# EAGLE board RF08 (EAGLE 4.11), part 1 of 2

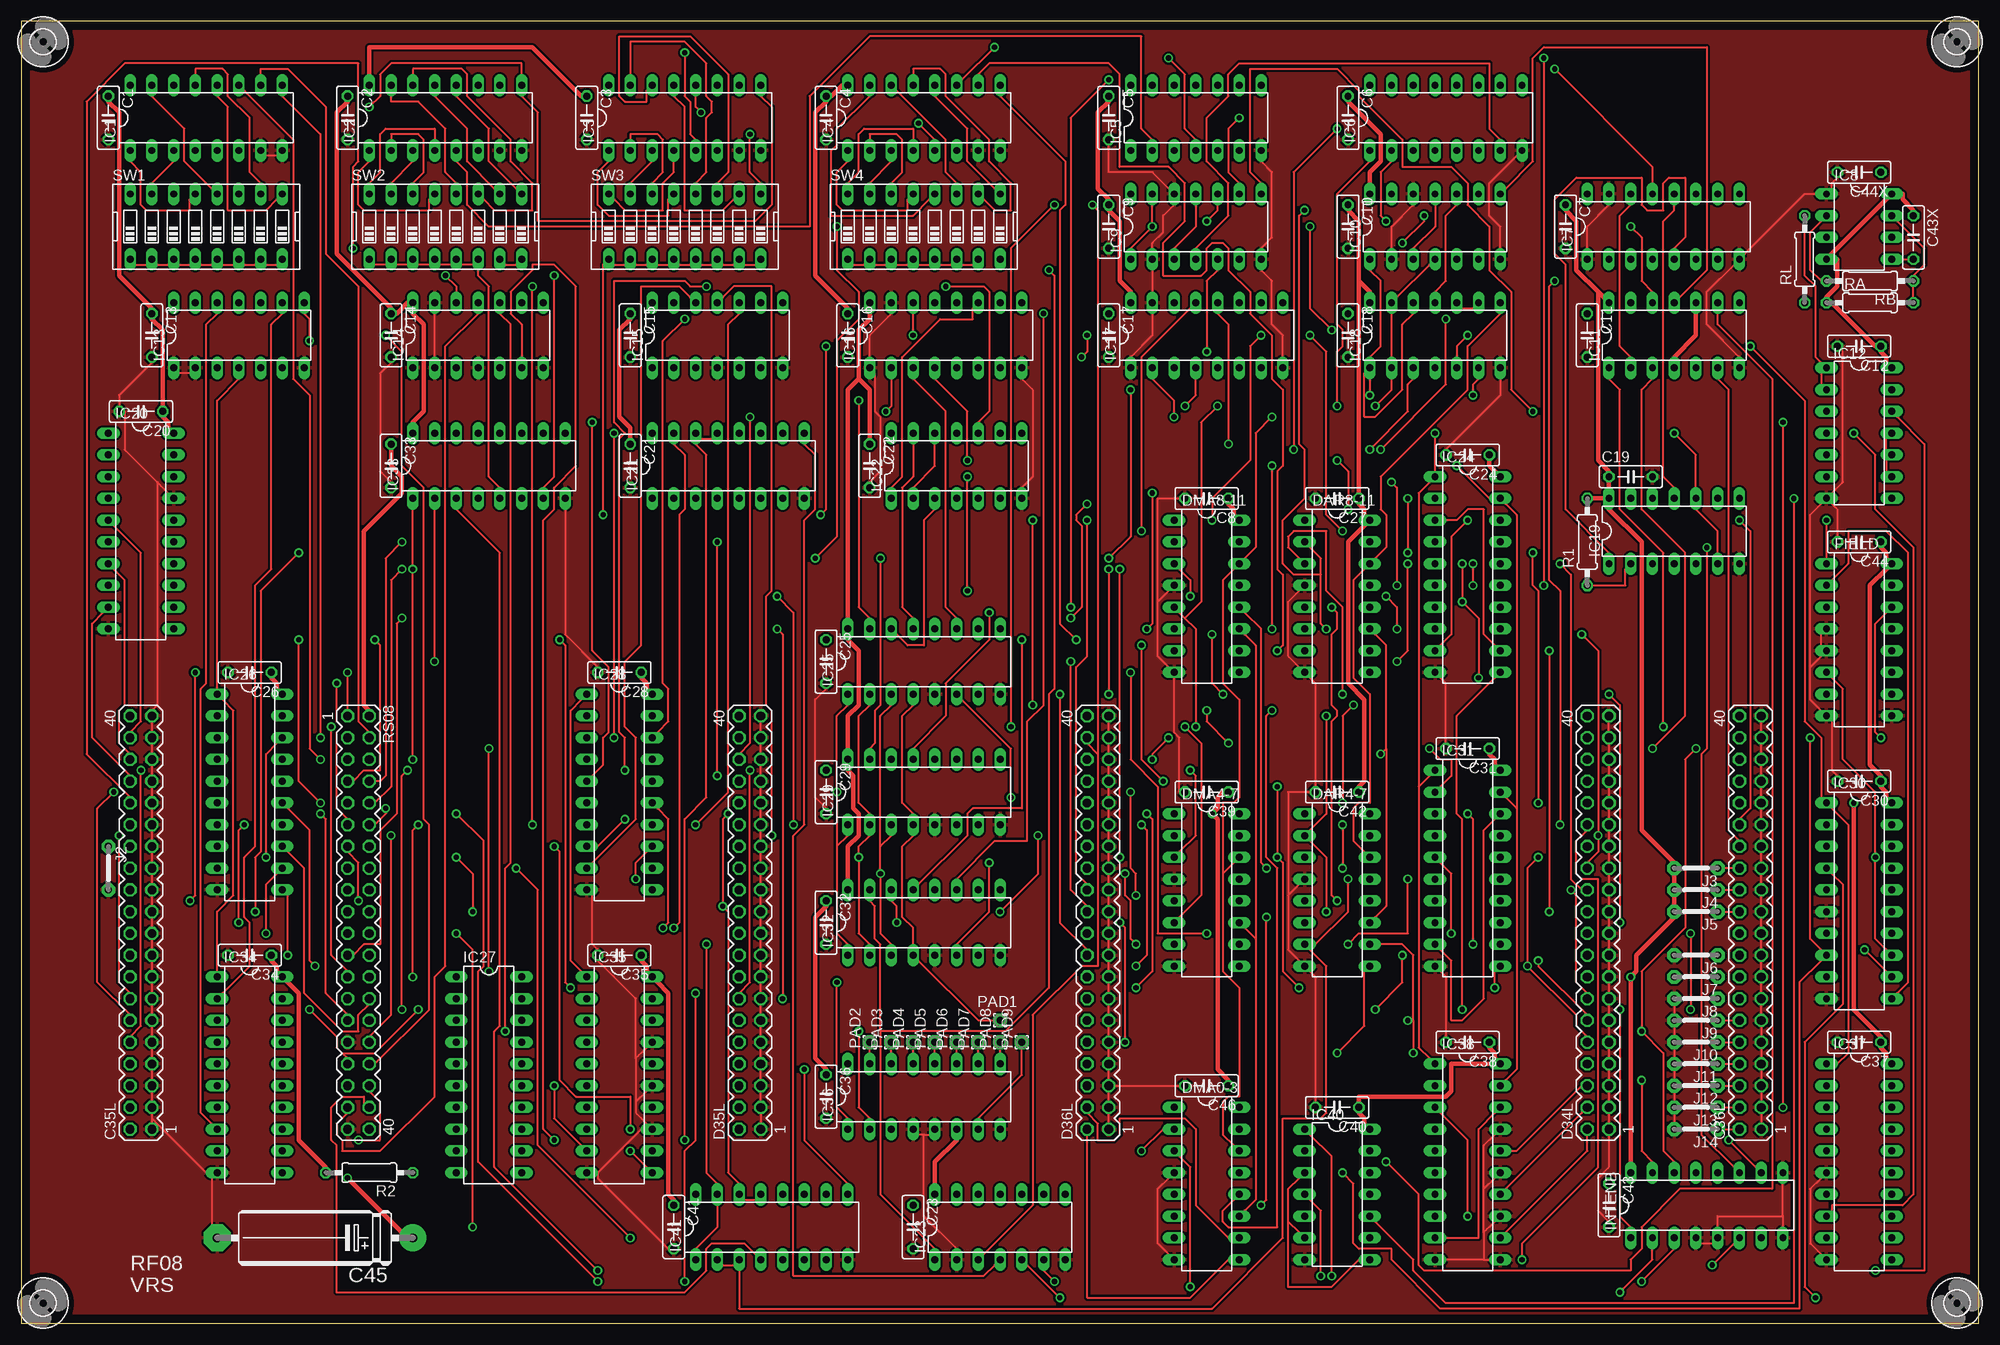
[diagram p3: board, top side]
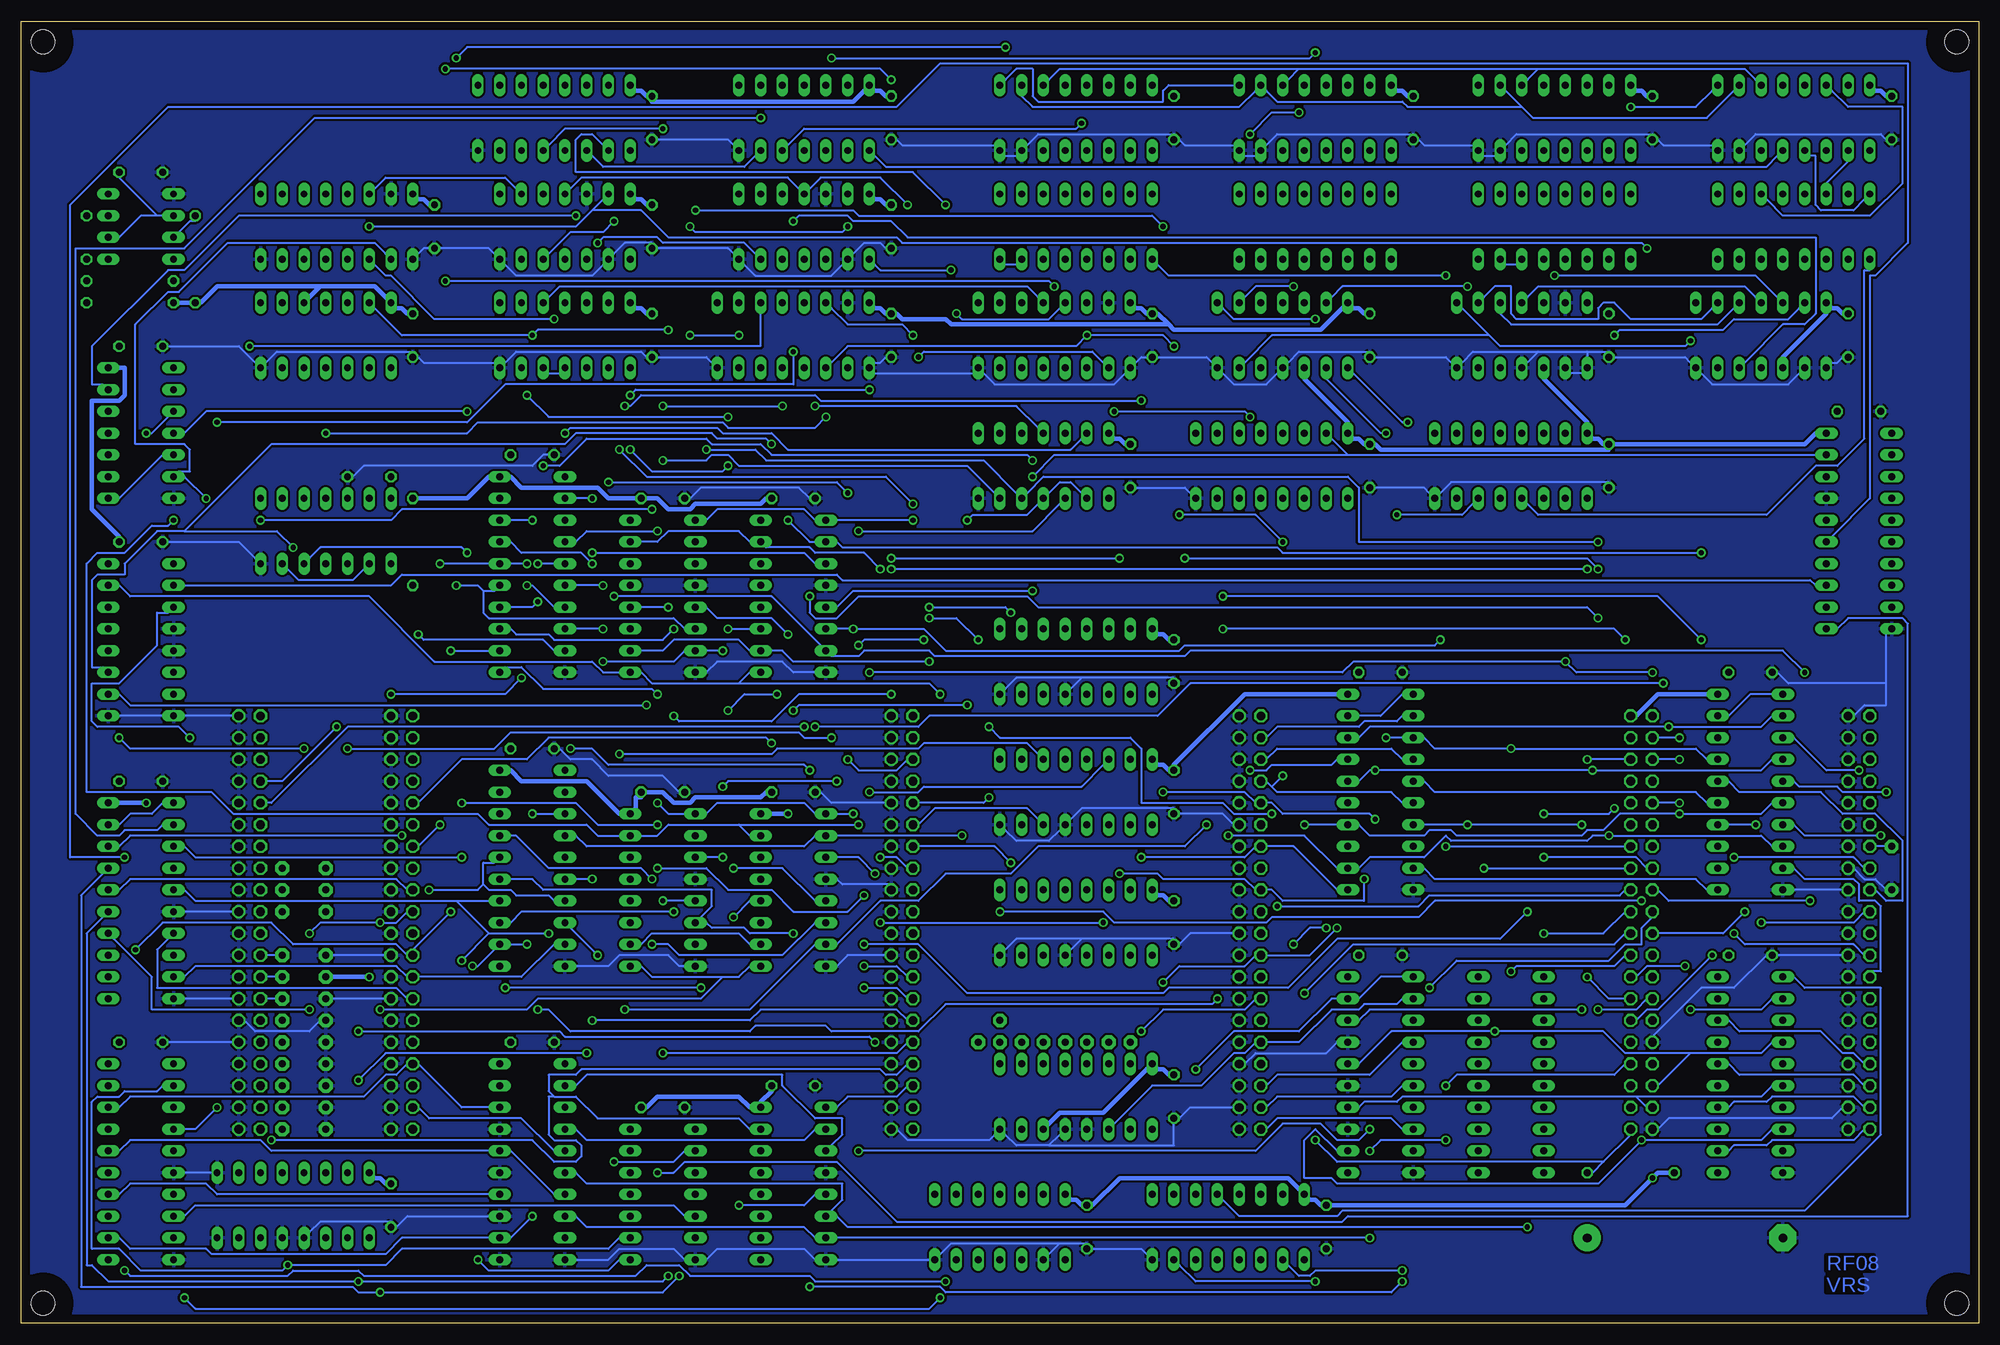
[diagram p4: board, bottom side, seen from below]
Size 228.58 x 152.07 mm. Coordinates in mm from the lower left corner, seen from the top.
Outline: 0,0 228.58,0 228.58,152.07 0,152.07 0,0
Copper layers (1*16): Top 0.035mm / dielectric 1.5mm / Bottom 0.035mm
Design rules "olimex10mil": minimum track width 10mil, minimum drill 24mil, track to track 10mil, track to pad 10mil, pad to pad 10mil, via to via 10mil, smd to smd 10mil, copper to edge 40mil, drill to drill 10mil, minimum pad ring 10mil, minimum via ring 8mil, stop-mask expansion 0mil, vias tented up to drill 0mil, thermal gap 10mil
Net classes: 1 Power: width 0.508 mm

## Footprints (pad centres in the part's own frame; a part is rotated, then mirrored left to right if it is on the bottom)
C050-025X075 = drill 0.813 octagon: 1 -2.54,0; 2 2.54,0
MA20-2 = drill 1.016 octagon: 1 -24.13,-1.27; 2 -24.13,1.27; 3 -21.59,-1.27; 4 -21.59,1.27; 5 -19.05,-1.27; 6 -19.05,1.27; 7 -16.51,-1.27; 8 -16.51,1.27; 9 -13.97,-1.27; 10 -13.97,1.27; 11 -11.43,-1.27; 12 -11.43,1.27; 13 -8.89,-1.27; 14 -8.89,1.27; 15 -6.35,-1.27; 16 -6.35,1.27; 17 -3.81,-1.27; 18 -3.81,1.27; 19 -1.27,-1.27; 20 -1.27,1.27; 21 1.27,-1.27; 22 1.27,1.27; 23 3.81,-1.27; 24 3.81,1.27; 25 6.35,-1.27; 26 6.35,1.27; 27 8.89,-1.27; 28 8.89,1.27; 29 11.43,-1.27; 30 11.43,1.27; 31 13.97,-1.27; 32 13.97,1.27; 33 16.51,-1.27; 34 16.51,1.27; 35 19.05,-1.27; 36 19.05,1.27; 37 21.59,-1.27; 38 21.59,1.27; 39 24.13,-1.27; 40 24.13,1.27
E22-6 = drill 1.016 pad 3.15 round: + -11.43,0 | drill 1.016 pad 3.15 octagon: - 11.43,0
DIL16 = drill 0.813 long: 1 -8.89,-3.81; 2 -6.35,-3.81; 3 -3.81,-3.81; 4 -1.27,-3.81; 5 1.27,-3.81; 6 3.81,-3.81; 7 6.35,-3.81; 8 8.89,-3.81; 9 8.89,3.81; 10 6.35,3.81; 11 3.81,3.81; 12 1.27,3.81; 13 -1.27,3.81; 14 -3.81,3.81; 15 -6.35,3.81; 16 -8.89,3.81
DIL14 = drill 0.813 long: 1 -7.62,-3.81; 2 -5.08,-3.81; 3 -2.54,-3.81; 4 0,-3.81; 5 2.54,-3.81; 6 5.08,-3.81; 7 7.62,-3.81; 8 7.62,3.81; 9 5.08,3.81; 10 2.54,3.81; 11 0,3.81; 12 -2.54,3.81; 13 -5.08,3.81; 14 -7.62,3.81
DIL08 = drill 0.813 long: 1 -3.81,-3.81; 2 -1.27,-3.81; 3 1.27,-3.81; 4 3.81,-3.81; 5 3.81,3.81; 6 1.27,3.81; 7 -1.27,3.81; 8 -3.81,3.81
DIL20 = drill 0.813 long: 1 -11.43,-3.81; 2 -8.89,-3.81; 3 -6.35,-3.81; 4 -3.81,-3.81; 5 -1.27,-3.81; 6 1.27,-3.81; 7 3.81,-3.81; 8 6.35,-3.81; 9 8.89,-3.81; 10 11.43,-3.81; 11 11.43,3.81; 12 8.89,3.81; 13 6.35,3.81; 14 3.81,3.81; 15 1.27,3.81; 16 -1.27,3.81; 17 -3.81,3.81; 18 -6.35,3.81; 19 -8.89,3.81; 20 -11.43,3.81
05 = drill 0.813 pad 1.6 octagon: 1 -2.54,0; 2 2.54,0
1,6/0,8 = drill 0.813 pad 1.6 octagon: 1 0,0
0207/10 = drill 0.813 octagon: 1 -5.08,0; 2 5.08,0
EDG-08 = drill 0.813 long: 1 -8.89,-3.81; 2 -6.35,-3.81; 3 -3.81,-3.81; 4 -1.27,-3.81; 5 1.27,-3.81; 6 3.81,-3.81; 7 6.35,-3.81; 8 8.89,-3.81; 9 8.89,3.81; 10 6.35,3.81; 11 3.81,3.81; 12 1.27,3.81; 13 -1.27,3.81; 14 -3.81,3.81; 15 -6.35,3.81; 16 -8.89,3.81
2,8 = hole 2.8: 0,0

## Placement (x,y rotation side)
C1  0.1  [C050-025X075]  10.15,140.81 270 top
C2  0.1  [C050-025X075]  38.09,140.81 270 top
C3  0.1  [C050-025X075]  66.04,140.81 270 top
C4  0.1  [C050-025X075]  93.98,140.81 270 top
C5  0.1  [C050-025X075]  127,140.81 270 top
C6  0.1  [C050-025X075]  154.94,140.81 270 top
C7  0.1  [C050-025X075]  180.34,128.11 270 top
C8  0.1  [C050-025X075]  138.43,96.35 180 top
C9  0.1  [C050-025X075]  127,128.11 270 top
C10  0.1  [C050-025X075]  154.94,128.11 270 top
C11  0.1  [C050-025X075]  182.88,115.4 270 top
C12  0.1  [C050-025X075]  214.62,114.13 180 top
C13  0.1  [C050-025X075]  15.23,115.4 270 top
C14  0.1  [C050-025X075]  43.17,115.4 270 top
C15  0.1  [C050-025X075]  71.12,115.4 270 top
C16  0.1  [C050-025X075]  96.52,115.4 270 top
C17  0.1  [C050-025X075]  127,115.4 270 top
C18  0.1  [C050-025X075]  154.94,115.4 270 top
C19  0.1  [C050-025X075]  187.96,98.89 0 top
C20  0.1  [C050-025X075]  13.96,106.52 180 top
C21  0.1  [C050-025X075]  71.12,100.16 270 top
C22  0.1  [C050-025X075]  99.06,100.16 270 top
C23  0.1  [C050-025X075]  104.14,11.27 270 top
C24  0.1  [C050-025X075]  168.91,101.43 180 top
C25  0.1  [C050-025X075]  93.98,77.3 270 top
C26  0.1  [C050-025X075]  26.67,76.03 180 top
C27  0.1  [C050-025X075]  153.66,96.35 180 top
C28  0.1  [C050-025X075]  69.84,76.03 180 top
C29  0.1  [C050-025X075]  93.98,62.06 270 top
C30  0.1  [C050-025X075]  214.62,63.34 180 top
C31  0.1  [C050-025X075]  168.91,67.14 180 top
C32  0.1  [C050-025X075]  93.98,46.83 270 top
C33  0.1  [C050-025X075]  43.17,100.16 270 top
C34  0.1  [C050-025X075]  26.67,43.02 180 top
C35  0.1  [C050-025X075]  69.84,43.02 180 top
C35L  [MA20-2]  13.96,46.83 90 top
C36  0.1  [C050-025X075]  93.98,26.51 270 top
C36L  [MA20-2]  201.93,46.83 90 top
C37  0.1  [C050-025X075]  214.62,32.86 180 top
C38  0.1  [C050-025X075]  168.91,32.86 180 top
C39  0.1  [C050-025X075]  138.43,62.06 180 top
C40  0.1  [C050-025X075]  153.66,25.23 180 top
C41  0.1  [C050-025X075]  76.2,11.27 270 top
C42  0.1  [C050-025X075]  153.66,62.06 180 top
C43  0.1  [C050-025X075]  185.41,13.81 270 top
C43X  .1uf  [C050-025X075]  220.97,126.83 270 top
C44  0.1  [C050-025X075]  214.62,91.27 180 top
C44X  .1uf  [C050-025X075]  214.62,134.46 180 top
C45  100uf  [E22-6]  34.28,10 180 top
C46  0.1  [C050-025X075]  138.43,27.78 180 top
D34L  [MA20-2]  184.15,46.83 90 top
D35L  [MA20-2]  85.09,46.83 90 top
D36L  [MA20-2]  125.73,46.83 90 top
DAR4-7  74LS193N  [DIL16]  153.66,50.63 270 top
DAR8-11  74LS193N  [DIL16]  153.66,84.92 270 top
DMA0-3  74LS193N  [DIL16]  138.43,16.35 270 top
DMA4-7  74LS193N  [DIL16]  138.43,50.63 270 top
DMA8-11  74LS193N  [DIL16]  138.43,84.92 270 top
FIELD  74LS193N  [DIL16]  214.62,79.84 270 top
IC1  74LS151N  [DIL16]  21.59,140.81 0 top
IC2  74LS151N  [DIL16]  49.52,140.81 0 top
IC3  74LS151N  [DIL16]  77.47,140.81 0 top
IC4  74LS151N  [DIL16]  105.41,140.81 0 top
IC5  74LS20N  [DIL14]  137.16,140.81 0 top
IC6  74S139N  [DIL16]  166.37,140.81 0 top
IC7  74LS139N  [DIL16]  191.77,128.11 0 top
IC8  LM555N  [DIL08]  214.62,128.11 270 top
IC9  74S74N  [DIL14]  137.16,128.11 0 top
IC10  74S74N  [DIL14]  165.09,128.11 0 top
IC11  74S74N  [DIL14]  193.03,115.4 0 top
IC12  74LS00N  [DIL14]  214.62,103.97 270 top
IC13  74180N  [DIL14]  25.39,115.4 0 top
IC14  74180N  [DIL14]  53.34,115.4 0 top
IC15  74180N  [DIL14]  81.28,115.4 0 top
IC16  74S139N  [DIL16]  107.95,115.4 0 top
IC17  74S139N  [DIL16]  138.43,115.4 0 top
IC18  74LS00N  [DIL14]  165.09,115.4 0 top
IC19  7407N  [DIL14]  193.03,92.54 0 top
IC20  74S240N  [DIL20]  13.96,92.54 270 top
IC21  74LS139N  [DIL16]  82.55,100.16 0 top
IC22  7407N  [DIL14]  109.22,100.16 0 top
IC23  74S74N  [DIL14]  114.3,11.27 0 top
IC24  74S240N  [DIL20]  168.91,87.46 270 top
IC25  74S138N  [DIL16]  105.41,77.3 0 top
IC26  74S240N  [DIL20]  26.67,62.06 270 top
IC27  SPARE  [DIL20]  54.6,29.05 270 top
IC28  74LS244N  [DIL20]  69.84,62.06 270 top
IC29  74S138N  [DIL16]  105.41,62.06 0 top
IC30  74S240N  [DIL20]  214.62,49.37 270 top
IC31  74S240N  [DIL20]  168.91,53.18 270 top
IC32  74S138N  [DIL16]  105.41,46.83 0 top
IC33  74LS139N  [DIL16]  54.6,100.16 0 top
IC34  74S240N  [DIL20]  26.67,29.05 270 top
IC35  74LS244N  [DIL20]  69.84,29.05 270 top
IC36  74S138N  [DIL16]  105.41,26.51 0 top
IC37  74S240N  [DIL20]  214.62,18.89 270 top
IC38  74S240N  [DIL20]  168.91,18.89 270 top
IC40  74S03N  [DIL14]  153.66,15.08 270 top
IC41  74LS139N  [DIL16]  87.62,11.27 0 top
INTENB  74LS193N  [DIL16]  196.84,13.81 0 top
J2  J5MM  [05]  10.15,53.18 270 top
J3  J5MM  [05]  195.58,53.18 180 top
J4  J5MM  [05]  195.58,50.63 180 top
J5  J5MM  [05]  195.58,48.09 180 top
J6  J5MM  [05]  195.58,43.02 180 top
J7  J5MM  [05]  195.58,40.48 180 top
J8  J5MM  [05]  195.58,37.94 180 top
J9  J5MM  [05]  195.58,35.4 180 top
J10  J5MM  [05]  195.58,32.86 180 top
J11  J5MM  [05]  195.58,30.32 180 top
J12  J5MM  [05]  195.58,27.78 180 top
J13  J5MM  [05]  195.58,25.23 180 top
J14  J5MM  [05]  195.58,22.7 180 top
PAD1  [1,6/0,8]  114.3,35.4 90 top
PAD2  [1,6/0,8]  99.06,32.86 90 top
PAD3  [1,6/0,8]  101.59,32.86 90 top
PAD4  [1,6/0,8]  104.14,32.86 90 top
PAD5  [1,6/0,8]  106.68,32.86 90 top
PAD6  [1,6/0,8]  109.22,32.86 90 top
PAD7  [1,6/0,8]  111.76,32.86 90 top
PAD8  [1,6/0,8]  114.3,32.86 90 top
PAD9  [1,6/0,8]  116.84,32.86 90 top
R1  4.7K  [0207/10]  182.88,91.27 90 top
R2  4.7K  [0207/10]  40.63,17.62 180 top
RA  470K  [0207/10]  215.9,119.21 0 top
RB  1.5K  [0207/10]  215.9,121.75 180 top
RL  1K  [0207/10]  208.28,124.29 90 top
RS08  [MA20-2]  39.36,46.83 270 top
SW1  [EDG-08]  21.59,128.11 0 top
SW2  [EDG-08]  49.52,128.11 0 top
SW3  [EDG-08]  77.47,128.11 0 top
SW4  [EDG-08]  105.41,128.11 0 top
U$1  [2,8]  2.54,149.7 0 top
U$2  [2,8]  226.06,149.7 0 top
U$3  [2,8]  2.54,2.38 0 top
U$4  [2,8]  226.06,2.38 0 top

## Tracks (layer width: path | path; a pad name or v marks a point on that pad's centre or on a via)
3CYC\
  Bottom 0.254: C35L.28 12.06,55.72 10.79,55.72 J2.1
601\  (via drill 0.61)
  Top 0.254: v168.91,115.4 167.63,114.13 167.63,112.86 IC18.5 | IC9.1 129.53,125.56 v132.08,128.11 132.08,130.65 IC9.13 | 100.33,34.12 100.33,15.08 106.68,8.73 IC23.1 | 100.33,34.12 100.33,44.29 99.69,44.92 99.69,48.73 99.06,49.37 IC32.15 | v120.01,123.02 120.65,122.39 120.65,74.13 120.01,73.49 120.01,39.2 114.93,34.12 100.33,34.12 | v153.03,116.04 150.49,118.58 v150.49,128.11
  Bottom 0.254: IC18.4 165.73,110.96 167,110.96 IC18.5 | IC11.13 187.32,118.58 184.15,115.4 v168.91,115.4 168.27,116.04 v153.03,116.04 | v120.01,123.02 128.27,123.02 128.9,123.66 IC9.1 | v150.49,128.11 149.86,127.47 132.71,127.47 v132.08,128.11
602\  (via drill 0.61)
  Top 0.254: v100.33,89.37 100.33,72.22 99.69,71.59 99.69,67.78 99.06,67.14 IC29.15 | v127,89.37 129.53,91.91 v129.53,109.05 | v157.47,108.42 157.47,110.32 IC18.1 | IC10.1 157.47,123.02 158.75,121.75 158.75,114.13 157.47,112.86 IC18.1 | IC18.12 162.56,117.94 161.28,116.67 161.28,109.05 158.11,105.88 156.84,105.88 156.84,110.96 IC18.1
  Bottom 0.254: v127,89.37 v100.33,89.37 | v129.53,109.05 156.84,109.05 v157.47,108.42
604\  (via drill 0.61)
  Top 0.254: v97.79,107.78 97.79,83.65 99.06,82.38 IC25.15 | v158.11,107.15 160.02,109.05 160.02,110.32 IC18.2 160.02,112.86 160.02,117.94 IC18.13 160.65,119.85 164.46,123.66 IC10.4
  Bottom 0.254: v97.79,107.78 135.25,107.78 135.88,108.42 156.21,108.42 157.47,107.15 v158.11,107.15
611\  (via drill 0.61)
  Top 0.254: v102.23,46.83 102.23,48.73 101.59,49.37 IC32.14 | v128.27,46.83 128.9,46.19 v128.9,32.86 | INTENB.14 193.03,18.89 191.77,20.16 191.77,31.59 v189.22,34.12 189.22,41.11 194.31,46.19 194.31,65.88 v195.58,67.14 | v217.16,68.41 216.53,69.05 216.53,81.75 217.8,83.02 FIELD.14
  Bottom 0.254: v128.27,46.83 v102.23,46.83 | v128.9,32.86 129.53,33.49 165.09,33.49 165.73,34.12 v189.22,34.12 | v217.16,68.41 215.9,67.14 v195.58,67.14
612\  (via drill 0.61)
  Top 0.254: v129.53,62.06 129.53,53.18 130.17,52.54 v130.17,50 | v154.3,58.26 v154.3,53.18 | v177.16,60.8 177.16,85.56 176.53,86.19 v176.53,90
  Bottom 0.254: v129.53,62.06 123.82,62.06 123.19,62.7 104.77,62.7 102.23,65.24 IC29.14 | v130.17,50 132.08,48.09 138.43,48.09 140.97,50.63 146.05,50.63 148.59,53.18 v154.3,53.18 | v154.3,58.26 161.28,58.26 163.83,60.8 v177.16,60.8 | v176.53,90 177.16,90.64 193.67,90.64 194.94,89.37 IC19.5
614\  (via drill 0.61)
  Top 0.254: IC25.14 102.23,80.48 103.5,79.21 105.41,79.21 105.41,93.81 106.68,95.08 IC22.3 | v130.81,92.54 130.81,112.86 136.52,118.58 IC17.13
  Bottom 0.254: v130.81,92.54 110.48,92.54 107.31,95.72 IC22.3
621\  (via drill 0.61)
  Top 0.254: v116.84,79.84 116.84,60.16 111.12,60.16 110.48,59.52 110.48,56.98 104.77,51.27 IC32.13 | v122.55,82.38 123.82,83.65 123.82,93.18 123.19,93.81 123.19,94.45 v124.45,95.72 | v158.75,102.07 166.37,109.69 v166.37,117.31
  Bottom 0.254: v116.84,79.84 119.38,82.38 v122.55,82.38 | v124.45,95.72 127.63,98.89 155.57,98.89 v158.75,102.07 | v166.37,117.31 180.34,117.31 185.41,122.39 186.05,122.39 187.32,123.66 IC7.3
622\  (via drill 0.61)
  Top 0.254: v113.03,83.02 113.03,79.84 107.95,74.77 107.95,70.95 104.14,67.14 IC29.13 | v122.55,83.65 122.55,140.81 v127,145.25 | v179.06,146.52 190.5,135.09 190.5,133.19 IC7.13
  Bottom 0.254: v113.03,83.02 113.66,83.65 v122.55,83.65 | v127,145.25 128.27,146.52 v179.06,146.52
624\  (via drill 0.61)
  Top 0.254: IC25.13 104.14,82.38 102.87,83.65 102.87,97.62 104.14,98.89 104.14,102.7 IC22.13 | 163.19,62.7 163.19,32.22 164.46,30.95 IC38.1 | 163.19,62.7 164.46,63.97 IC31.1 | 163.19,62.7 163.19,96.99 164.46,98.26 IC24.1 165.09,99.53 v165.09,103.97
  Bottom 0.254: v165.09,103.97 164.46,104.61 147.31,104.61 146.68,103.97 140.97,103.97 139.06,102.07 106.04,102.07 104.77,103.34 IC22.13
641\  (via drill 0.61)
  Top 0.254: v119.38,117.94 119.38,72.22 117.47,70.32 117.47,56.35 113.66,56.35 109.22,51.91 IC32.11
  Bottom 0.254: v119.38,117.94 118.74,117.31 108.58,117.31 107.31,118.58 IC16.13
642\  (via drill 0.61)
  Top 0.254: v158.75,66.51 159.38,67.14 | 159.38,67.14 159.38,79.21 158.11,80.48 DAR8-11.11 | 159.38,67.14 159.38,48.73 158.11,47.46 DAR4-7.11
  Bottom 0.254: v158.75,66.51 140.97,66.51 140.33,67.14 123.82,67.14 123.19,67.78 111.12,67.78 109.85,66.51 IC29.11
644\
  Top 0.254: IC25.11 109.22,82.38 107.95,83.65 107.95,106.52 104.14,110.32 IC16.3
645\  (via drill 0.61)
  Top 0.254: 174.62,60.16 174.62,29.68 173.35,28.41 IC38.19 | 174.62,60.16 173.35,61.43 IC31.19 | 174.62,60.16 174.62,94.45 173.35,95.72 IC24.19 171.44,96.35 v167.63,100.16 | v110.48,100.8 110.48,106.52 106.68,110.32 IC16.4
  Bottom 0.254: v110.48,100.8 111.12,101.43 140.97,101.43 142.24,102.7 147.95,102.7 148.59,103.34 162.56,103.34 165.73,100.16 v167.63,100.16
ACB00\  (via drill 0.61)
  Top 0.254: IC38.12 173.35,10.63 182.88,20.16 182.88,22.06 D34L.2 | v168.91,12.54 168.91,21.43 165.73,24.6 IC38.3
  Bottom 0.254: v168.91,12.54 171.44,10 IC38.12 173.99,10 184.15,10 186.05,8.09 206.37,8.09 207,8.73 215.9,8.73 217.16,10 IC37.12
ACB01\
  Top 0.254: IC38.14 173.35,15.71 182.24,24.6 182.24,25.23 D34L.4
  Bottom 0.254: IC37.14 217.16,15.08 215.9,16.35 207,16.35 205.74,15.08 173.99,15.08 IC38.14 | IC38.5 166.37,20.16 170.18,23.96 180.97,23.96 182.24,25.23 D34L.4
ACB02\
  Top 0.254: D34L.6 182.24,27.78 174.62,20.16 173.99,20.16 IC38.16
  Bottom 0.254: IC38.7 166.37,15.08 171.44,20.16 IC38.16 173.99,20.16 199.38,20.16 200.66,21.43 215.9,21.43 217.16,20.16 IC37.16
ACB03\
  Top 0.254: IC38.9 166.37,10 170.18,10 170.18,22.7 172.08,24.6 IC38.18
  Bottom 0.254: IC37.18 217.16,25.23 215.9,26.51 188.59,26.51 186.05,29.05 184.78,29.05 183.51,30.32 D34L.8 182.24,30.32 177.16,25.23 173.99,25.23 IC38.18
ACB04\  (via drill 0.61)
  Top 0.254: D34L.10 182.88,33.49 181.61,34.76 181.61,36.03 v175.89,41.74 175.89,53.18 v177.16,54.45 | v168.91,59.52 169.54,58.89 v169.54,44.29
  Bottom 0.254: v175.89,41.74 175.25,41.74 173.35,43.65 IC31.12 171.44,44.29 v169.54,44.29 | v177.16,54.45 208.28,54.45 209.55,55.72 IC30.3 | v168.91,59.52 166.37,59.52 IC31.3
ACB05\  (via drill 0.61)
  Top 0.254: v167,45.55 167,52.54 165.73,53.81 IC31.5 | v177.16,42.38 177.16,41.74 182.88,36.03 D34L.12
  Bottom 0.254: 177.8,49.37 208.28,49.37 209.55,50.63 IC30.5 | 177.8,49.37 173.99,49.37 IC31.14 | 173.99,45.55 v167,45.55 | 177.8,49.37 173.99,45.55 | 173.99,45.55 v177.16,42.38
ACB06\  (via drill 0.61)
  Top 0.254: v180.97,50.63 181.61,50 181.61,39.84 182.88,38.57 D34L.14
  Bottom 0.254: 174.62,51.27 173.99,50.63 171.44,50.63 170.81,50 167,50 166.37,49.37 IC31.7 | 174.62,51.27 174.62,53.81 173.35,53.81 IC31.16 | IC30.7 211.45,44.92 212.72,43.65 212.72,39.2 184.78,39.2 183.51,37.94 D34L.14 | 174.62,51.27 175.25,50.63 v180.97,50.63
ACB07\
  Top 0.254: IC31.18 172.08,58.89 170.81,57.62 170.81,37.94 168.27,35.4 167,35.4 167,42.38 165.73,43.65 IC31.9
  Bottom 0.254: IC30.9 209.55,40.48 208.28,41.74 184.78,41.74 183.51,40.48 D34L.16 182.24,40.48 170.18,40.48 166.37,44.29 IC31.9
ACB08\  (via drill 0.61)
  Top 0.254: IC24.3 166.37,93.81 167.63,93.81 168.91,95.08 170.81,95.08 170.81,80.48 172.08,79.21 IC24.12 | v215.26,43.65 217.8,41.11 IC30.12 | v178.43,78.57 v178.43,48.09
  Bottom 0.254: v215.26,43.65 212.09,46.83 199.38,46.83 196.84,44.29 184.78,44.29 183.51,43.02 D34L.18 182.88,43.65 v178.43,48.09 | v178.43,78.57 173.99,78.57 IC24.12
ACB09\  (via drill 0.61)
  Top 0.254: v168.27,88.73 v168.27,84.29 170.18,82.38 v170.18,75.4 | v194.94,45.55 v194.94,36.66 | v185.41,73.49 186.69,72.22 v186.69,46.83
  Bottom 0.254: v168.27,88.73 166.37,88.73 IC24.5 | v168.27,84.29 168.91,83.65 171.44,83.65 IC24.14 | v194.94,36.66 213.36,36.66 213.36,40.48 217.8,44.92 IC30.14 | v194.94,45.55 193.67,46.83 v186.69,46.83 184.78,46.83 183.51,48.09 D34L.22 | v170.18,75.4 172.08,73.49 v185.41,73.49
ACB10\  (via drill 0.61)
  Top 0.254: v169.54,86.19 v169.54,88.73 | v179.7,88.73 180.97,87.46 180.97,51.91 182.24,50.63 D34L.24
  Bottom 0.254: v169.54,86.19 168.91,86.19 166.37,83.65 IC24.7 | v169.54,88.73 171.44,88.73 IC24.16 173.99,88.73 v179.7,88.73 | IC30.16 217.16,50.63 215.9,51.91 184.78,51.91 183.51,50.63 D34L.24
ACB11\  (via drill 0.61)
  Top 0.254: v168.91,93.81 167,91.91 167,80.48 165.73,79.21 IC24.9 | D34L.26 182.88,53.81 184.15,55.08 v184.15,56.98 184.15,78.57 v182.24,80.48
  Bottom 0.254: v168.91,93.81 171.44,93.81 IC24.18 | v184.15,56.98 215.9,56.98 217.16,55.72 IC30.18 | v182.24,80.48 181.61,79.84 167.63,79.84 166.37,78.57 IC24.9
ACCLEAR\  (via drill 0.61)
  Top 0.254: IC22.2 104.14,97.62 106.68,100.16 106.68,102.7 IC22.12 | v140.97,67.78 138.43,70.32 v138.43,71.59 | v118.11,72.22 v118.11,93.81
  Bottom 0.254: IC22.2 104.77,96.99 106.04,98.26 107.31,98.26 108.58,96.99 IC22.4 109.85,95.72 111.12,94.45 117.47,94.45 v118.11,93.81 | v140.97,67.78 141.6,68.41 167,68.41 169.54,65.88 177.16,65.88 182.24,60.8 D34L.32 | v138.43,71.59 137.79,72.22 v118.11,72.22
BAC00
  Top 0.254: DMA0-3.9 140.97,7.46 136.52,3.01 124.45,3.01 124.45,22.06 D36L.2
BAC01
  Top 0.254: DMA0-3.10 140.97,10 137.16,13.81 137.16,22.7 135.88,23.96 128.27,23.96 128.27,22.06 127.63,21.43 125.73,21.43 125.73,23.33 124.45,24.6 D36L.4
BAC02
  Bottom 0.254: DMA0-3.1 133.34,25.23 132.08,26.51 126.36,26.51 125.09,27.78 D36L.6
BAC03  (via drill 0.61)
  Top 0.254: v199.38,21.43 202.56,18.25 INTENB.10
  Bottom 0.254: 166.37,26.51 163.83,26.51 161.28,23.96 144.78,23.96 143.5,22.7 DMA0-3.15 | 166.37,26.51 167,27.14 167,29.05 163.83,29.05 163.19,29.68 128.27,29.68 127.63,29.05 126.36,29.05 125.09,30.32 D36L.8 | v199.38,21.43 168.91,21.43 166.37,18.89 163.83,18.89 163.19,19.52 163.19,20.79 163.83,21.43 166.37,21.43 167,22.06 167,26.51 166.37,26.51
BAC04  (via drill 0.61)
  Top 0.254: v186.69,36.66 186.69,12.54 187.96,11.27 INTENB.1 | v153.66,31.59 156.84,34.76 156.84,41.11 DAR4-7.9
  Bottom 0.254: 146.68,40.48 154.94,40.48 156.21,41.74 DAR4-7.9 | 146.68,40.48 144.78,40.48 143.5,41.74 DMA4-7.9 | v186.69,36.66 169.54,36.66 168.27,37.94 149.22,37.94 146.68,40.48 | v153.66,31.59 126.36,31.59 125.09,32.86 D36L.10
BAC05  (via drill 0.61)
  Top 0.254: v189.22,28.41 189.22,20.16 190.5,18.89 INTENB.15 | 162.56,35.4 162.56,43.02 161.28,44.29 158.75,44.29 DAR4-7.10 | 162.56,35.4 v162.56,31.59 | v161.92,35.4 162.56,35.4
  Bottom 0.254: DMA4-7.10 143.5,44.29 144.78,45.55 154.94,45.55 156.21,44.29 DAR4-7.10 | v189.22,28.41 186.05,31.59 v162.56,31.59 | v161.92,35.4 143.5,35.4 142.24,36.66 126.36,36.66 125.09,35.4 D36L.12
BAC06  (via drill 0.61)
  Top 0.254: v155.57,72.22 154.3,70.95 v154.3,60.8 | v130.17,39.2 132.08,41.11 132.08,58.89 v131.44,59.52
  Bottom 0.254: v155.57,72.22 215.9,72.22 217.16,73.49 FIELD.10 | v154.3,60.8 153.03,59.52 151.12,59.52 DAR4-7.1 148.59,59.52 147.31,60.8 137.16,60.8 135.88,59.52 DMA4-7.1 133.34,59.52 v131.44,59.52 | v130.17,39.2 126.36,39.2 125.09,37.94 D36L.14
BAC07  (via drill 0.61)
  Top 0.254: v210.81,93.81 210.81,89.37 FIELD.1 | v130.17,41.74 131.44,43.02 131.44,57.62 v130.81,58.26
  Bottom 0.254: 144.78,58.26 143.5,56.98 DMA4-7.15 | 144.78,58.26 153.03,58.26 154.3,56.98 156.21,56.98 DAR4-7.15 158.75,56.98 161.28,56.98 162.56,58.26 173.99,58.26 175.25,59.52 203.83,59.52 206.37,62.06 220.97,62.06 220.97,88.73 219.71,90 216.53,90 213.36,93.18 211.45,93.18 v210.81,93.81 | v130.17,41.74 126.36,41.74 125.09,40.48 D36L.16 | 144.78,58.26 v130.81,58.26
BAC08  (via drill 0.61)
  Top 0.254: v121.28,73.49 121.28,46.83 124.45,43.65 D36L.18
  Bottom 0.254: 144.78,74.77 143.5,76.03 DMA8-11.9 | 144.78,74.77 154.94,74.77 156.21,76.03 DAR8-11.9 158.75,76.03 160.65,76.03 161.92,77.3 180.34,77.3 187.96,84.92 215.9,84.92 217.16,86.19 FIELD.15 | v121.28,73.49 122.55,74.77 144.78,74.77
BAC09  (via drill 0.61)
  Top 0.254: v122.55,77.3 122.55,50.63 124.45,48.73 D36L.22
  Bottom 0.254: DAR8-11.10 156.21,78.57 153.66,78.57 152.4,79.84 144.78,79.84 143.5,78.57 DMA8-11.10 140.97,78.57 139.69,78.57 138.43,77.3 v122.55,77.3
BAC10  (via drill 0.61)
  Top 0.254: v124.45,93.81 124.45,77.94 123.19,76.67 123.19,52.54 124.45,51.27 D36L.24
  Bottom 0.254: DAR8-11.1 148.59,93.81 147.31,95.08 137.16,95.08 135.88,93.81 DMA8-11.1 133.34,93.81 v124.45,93.81
BAC11  (via drill 0.61)
  Top 0.254: v128.27,54.45 v128.27,88.1
  Bottom 0.254: DAR8-11.15 156.21,91.27 154.3,91.27 153.03,92.54 144.78,92.54 143.5,91.27 DMA8-11.15 141.6,90.64 136.52,90.64 135.88,90 130.17,90 v128.27,88.1 | v128.27,54.45 126.36,54.45 125.09,53.18 D36L.26
BADDAC\  (via drill 0.61)
  Top 0.254: v191.77,69.68 191.77,90 186.69,95.08 186.69,109.05 185.41,110.32 IC11.1
  Bottom 0.254: v191.77,69.68 198.12,63.34 200.02,63.34 C36L.34
BBREAK\  (via drill 0.61)
  Top 0.254: 135.88,82.38 137.16,81.11 v137.16,69.68 | 135.88,82.38 135.25,83.02 DMA8-11.5 | v153.66,107.15 153.66,113.5 154.3,114.13 154.3,116.04 153.66,116.67 153.66,131.92 157.47,135.72 IC6.1 | v139.69,107.15 137.79,105.24 137.79,84.29 135.88,82.38 | IC41.1 78.73,8.73 81.28,11.27 81.28,13.81 IC41.15 81.28,16.35 80.01,17.62 v80.01,44.29 | v76.2,46.19 76.83,46.83 76.83,94.45 77.47,95.08 77.47,101.43 76.2,102.7 IC21.15 | v110.48,85.56 v110.48,98.89
  Bottom 0.254: v137.16,69.68 190.5,69.68 199.38,60.8 200.02,60.8 C36L.32 | v153.66,107.15 v139.69,107.15 | 73.66,101.43 19.05,101.43 IC20.19 | 73.66,101.43 75.56,103.34 IC21.15 | v80.01,44.29 78.1,46.19 v76.2,46.19 | v110.48,85.56 131.44,85.56 133.34,83.65 DMA8-11.5 | v110.48,98.89 107.95,101.43 73.66,101.43
BINIT  (via drill 0.61)
  Top 0.254: IC9.3 134.62,125.56 137.16,128.11 137.16,130.65 IC9.11 | IC10.3 162.56,125.56 165.09,128.11 165.09,130.65 IC10.11 | 125.73,66.51 125.73,41.74 123.82,41.74 118.11,36.03 118.11,13.81 112.39,8.09 IC23.3 | 125.73,66.51 124.45,67.78 D36L.38 | v125.09,130.65 125.73,130.01 125.73,66.51
  Bottom 0.254: IC10.11 164.46,132.55 163.19,133.82 139.06,133.82 137.79,132.55 IC9.11 136.52,132.55 135.25,133.82 128.27,133.82 v125.09,130.65
BIOP1  (via drill 0.61)
  Top 0.254: v113.03,53.81 113.03,48.09 109.22,44.29 IC32.6
  Bottom 0.254: v113.03,53.81 114.93,55.72 123.82,55.72 D36L.28
BIOP2
  Bottom 0.254: IC29.6 109.85,58.89 111.12,60.16 121.92,60.16 123.82,58.26 D36L.30
BIOP4  (via drill 0.61)
  Top 0.254: v115.56,61.43 115.56,67.14 109.85,72.86 IC25.6
  Bottom 0.254: v115.56,61.43 116.2,60.8 123.82,60.8 D36L.32
BMB00
  Bottom 0.254: IC35.8 67.31,22.7 68.58,23.96 81.91,23.96 83.18,22.7 D35L.2
BMB01
  Bottom 0.254: IC35.6 67.31,27.78 68.58,26.51 81.91,26.51 83.18,25.23 D35L.4
BMB02
  Bottom 0.254: IC35.4 67.31,32.86 71.12,29.05 81.91,29.05 83.18,27.78 D35L.6
BMB03
  Bottom 0.254: IC35.2 67.31,37.94 67.94,37.3 71.75,37.3 72.39,36.66 75.56,36.66 79.37,32.86 83.18,32.86 D35L.10 84.45,32.86 85.72,31.59 86.99,31.59 90.8,27.78 96.52,27.78 100.96,23.33 IC36.3
BMB04  (via drill 0.61)
  Top 0.254: v97.79,34.12 97.79,25.23 99.06,23.96 IC36.2 | v85.09,64.6 85.09,39.84 83.81,38.57 D35L.14
  Bottom 0.254: v97.79,34.12 95.25,36.66 85.72,36.66 84.45,37.94 D35L.14 | v85.09,64.6 83.18,64.6 82.55,65.24 75.56,65.24 74.93,65.88 IC28.17
BMB05  (via drill 0.61)
  Top 0.254: v95.25,39.84 95.25,25.23 96.52,23.96 IC36.1 | v74.93,46.19 75.56,46.83 75.56,58.89 74.29,60.16 IC28.15
  Bottom 0.254: v95.25,39.84 93.34,41.74 85.72,41.74 84.45,43.02 D35L.18 83.18,43.02 78.1,43.02 v74.93,46.19
BMB06  (via drill 0.61)
  Top 0.254: v71.75,51.91 71.75,53.81 73.02,55.08 IC28.13 | 100.33,55.72 v100.33,52.54 100.33,45.55 101.59,44.29 IC32.3 | 100.33,55.72 101.59,56.98 IC29.3 | 100.33,55.72 100.33,70.95 101.59,72.22 IC25.3
  Bottom 0.254: v71.75,51.91 71.75,49.37 81.28,49.37 82.55,50.63 83.18,50.63 D35L.24 84.45,50.63 85.72,51.91 95.25,51.91 95.88,52.54 v100.33,52.54
BMB07  (via drill 0.61)
  Top 0.254: IC32.2 99.06,44.29 97.79,45.55 v97.79,54.45 97.79,55.72 99.06,56.98 IC29.2 99.06,59.52 97.79,60.8 97.79,70.95 99.06,72.22 IC25.2
  Bottom 0.254: IC28.11 74.93,50.63 80.01,55.72 83.18,55.72 D35L.28 84.45,55.72 85.72,54.45 v97.79,54.45
BMB08  (via drill 0.61)
  Top 0.254: v70.48,58.89 67.31,55.72 IC28.8 | 95.25,55.72 95.25,45.55 96.52,44.29 IC32.1 | 95.25,55.72 96.52,56.98 IC29.1 | 95.25,55.72 v95.25,62.06 95.25,70.95 96.52,72.22 IC25.1
  Bottom 0.254: v70.48,58.89 71.12,59.52 81.28,59.52 82.55,60.8 83.18,60.8 D35L.32 84.45,60.8 85.72,62.06 v95.25,62.06
BMB09  (via drill 0.61)
  Top 0.254: v104.14,115.4 104.14,117.94 IC16.14 | v81.28,63.97 v81.28,91.27 | v93.34,94.45 93.98,95.08 v93.98,114.13
  Bottom 0.254: 82.55,62.7 83.18,63.34 D35L.34 | 82.55,62.7 81.91,62.06 68.58,62.06 67.31,60.8 IC28.6 | IC17.3 133.98,112.23 132.08,114.13 105.41,114.13 v104.14,115.4 95.25,115.4 v93.98,114.13 | 82.55,62.7 v81.28,63.97 | v81.28,91.27 84.45,94.45 v93.34,94.45
BMB10  (via drill 0.61)
  Top 0.254: v123.82,112.86 124.45,113.5 v124.45,115.4 | v85.09,105.88 85.09,67.78 83.81,66.51 D35L.36 | v100.96,106.52 101.59,107.15 101.59,110.32 IC16.2
  Bottom 0.254: IC28.4 67.31,65.88 68.58,67.14 81.91,67.14 83.18,65.88 D35L.36 | v123.82,112.86 123.19,113.5 103.5,113.5 102.23,112.23 IC16.2 | v124.45,115.4 125.73,116.67 132.08,116.67 133.98,118.58 IC17.14 | v85.09,105.88 85.72,106.52 v100.96,106.52
BMB11
  Bottom 0.254: IC28.2 67.31,70.95 67.94,70.32 71.75,70.32 72.39,69.68 81.91,69.68 83.18,68.41 D35L.38
BRK_RQ\
  Top 0.254: IC11.6 198.12,110.32 199.38,109.05 199.38,57.62 200.66,56.35 C36L.28
BTS1  (via drill 0.61)
  Top 0.254: v190.5,67.14 194.31,70.95 194.31,90 189.22,95.08 189.22,109.05 190.5,110.32 IC11.3 | v133.98,68.41 132.08,66.51 v132.08,65.88
  Bottom 0.254: v190.5,67.14 173.35,67.14 171.44,69.05 137.79,69.05 137.16,68.41 v133.98,68.41 | v132.08,65.88 130.81,64.6 126.36,64.6 125.09,65.88 D36L.36
BUSY
  Top 0.254: IC11.2 187.96,112.86 186.69,114.13 186.69,129.38 187.96,130.65 IC7.14
  Bottom 0.254: IC10.9 170.81,132.55 172.08,133.82 186.05,133.82 187.32,132.55 IC7.14
BWCO\  (via drill 0.61)
  Top 0.254: v187.96,128.11 189.22,126.83 189.22,121.75 190.5,120.48 IC11.12 | v38.73,125.56 38.73,135.09 39.36,135.72 39.36,147.16 12.06,147.16 7.62,142.71 7.62,66.51 12.69,61.43 C35L.32
  Bottom 0.254: 161.92,130.01 163.83,128.11 v187.96,128.11 | 161.92,130.01 160.65,131.28 IC10.13 | v38.73,125.56 39.36,126.2 125.73,126.2 126.36,126.83 153.03,126.83 156.21,130.01 161.92,130.01
CIE  (via drill 0.61)
  Top 0.254: v153.03,5.55 153.03,19.52 150.49,22.06 IC40.1 | v189.22,4.92 193.03,8.73 INTENB.3
  Bottom 0.254: v153.03,5.55 153.66,4.92 v189.22,4.92 218.44,4.92 220.34,6.82 220.97,6.82 220.97,45.55 219.07,47.46 IC30.15
DA00\
  Top 0.254: C36L.2 200.02,22.7 198.75,22.7 J14.1
DA01\
  Top 0.254: C36L.4 200.02,25.23 198.75,25.23 J13.1
DA02\
  Top 0.254: C36L.6 200.02,27.78 198.75,27.78 J12.1
DA03\
  Top 0.254: C36L.8 200.02,30.32 198.75,30.32 J11.1
DA04\
  Top 0.254: C36L.10 200.02,32.86 198.75,32.86 J10.1
DA05\
  Top 0.254: C36L.12 200.02,35.4 198.75,35.4 J9.1
DA06\
  Bottom 0.254: C36L.14 200.02,37.94 198.75,37.94 J8.1
DA07\
  Bottom 0.254: C36L.16 200.02,40.48 198.75,40.48 J7.1
DA08\
  Bottom 0.254: C36L.18 200.02,43.02 198.75,43.02 J6.1
DA09\
  Top 0.254: C36L.22 200.02,48.09 198.75,48.09 J5.1
DA10\
  Top 0.254: C36L.24 200.02,50.63 198.75,50.63 J4.1
DA11\
  Top 0.254: C36L.26 200.02,53.18 198.75,53.18 J3.1
DAR04  (via drill 0.61)
  Top 0.254: v154.94,51.91 154.94,48.09 151.12,44.29 DAR4-7.7 150.49,43.65 152.4,41.74 152.4,24.6 151.76,23.96 147.31,23.96 147.31,10 139.06,1.74 83.81,1.74 83.81,6.18 IC41.3 83.18,6.82 81.91,6.82 IC41.2 | v67.31,6.18 55.24,18.25 55.24,34.12 55.88,34.76 55.88,90 50.79,95.08 IC33.3
  Bottom 0.254: v154.94,51.91 156.21,53.18 167,53.18 170.81,56.98 171.44,56.98 IC31.17 | v67.31,6.18 77.47,6.18 78.1,5.55 79.37,5.55 80.64,6.82 IC41.2
DAR05  (via drill 0.61)
  Top 0.254: v48.25,77.3 48.25,95.08 IC33.2 | v38.09,76.03 38.09,71.59 RS08.1 | v138.43,45.55 132.71,45.55 132.71,62.7 129.53,65.88 v129.53,76.03
  Bottom 0.254: IC31.15 171.44,51.91 168.91,51.91 167.63,50.63 147.95,50.63 147.95,48.73 149.22,47.46 DAR4-7.6 148.59,46.83 147.95,46.19 144.14,46.19 143.5,45.55 v138.43,45.55 | v38.09,76.03 46.98,76.03 v48.25,77.3 73.02,77.3 74.29,76.03 v129.53,76.03
DAR06  (via drill 0.61)
  Top 0.254: v152.4,48.09 152.4,54.45 150.49,56.35 DAR4-7.2 150.49,57.62 152.4,59.52 v152.4,70.95 | v45.71,65.88 v45.71,88.1 45.71,95.08 IC33.1 | v127,88.1 v127,73.49
  Bottom 0.254: v152.4,48.09 170.18,48.09 171.44,46.83 IC31.13 | v45.71,65.88 41.27,65.88 RS08.6 | v152.4,70.95 151.76,70.32 140.97,70.32 137.79,73.49 v127,73.49 | v45.71,88.1 v127,88.1
DAR07  (via drill 0.61)
  Top 0.254: v149.22,39.2 147.31,41.11 147.31,53.81 v146.68,54.45 v146.68,62.7 | v172.08,39.2 172.08,41.11 IC31.11 | v40.63,142.08 41.9,143.34 41.9,145.89 43.17,147.16 58.41,147.16 58.41,145.89 IC2.9 58.41,143.34 60.32,141.44 60.32,128.74 85.72,128.74 87.62,130.65 87.62,142.08 86.36,143.34 IC3.9 | v34.92,68.41 34.92,138.9 30.48,143.34 IC1.9 | v133.34,63.34 130.81,65.88 v130.81,79.21 | v123.19,79.84 121.28,81.75 121.28,130.01 121.92,130.65 121.92,135.72 114.3,143.34 IC4.9
  Bottom 0.254: v146.68,54.45 148.59,54.45 DAR4-7.3 | v149.22,39.2 v172.08,39.2 | IC3.9 86.99,144.62 94.61,144.62 95.25,143.98 95.25,142.71 109.85,142.71 110.48,143.34 110.48,146.52 112.39,146.52 113.66,145.25 IC4.9 | v40.63,142.08 33.02,142.08 31.11,143.98 IC1.9 | v34.92,68.41 37.46,68.41 RS08.3 | v146.68,62.7 146.05,63.34 v133.34,63.34 | v130.81,79.21 130.17,79.84 v123.19,79.84
DAR08  (via drill 0.61)
  Top 0.254: v160.65,77.3 161.92,78.57 v161.92,88.73 | RS08.4 40.63,69.05 39.36,70.32 39.36,121.12 35.55,124.93 35.55,142.08 31.11,146.52 27.94,146.52 27.94,145.89 IC1.10 | v146.68,78.57 147.31,79.21 147.31,87.46 146.68,88.1 146.68,99.53 147.31,100.16 147.31,109.05 146.05,110.32 146.05,115.4 143.5,117.94 143.5,120.48 140.97,123.02 140.97,125.56 140.33,126.2 139.06,126.2 138.43,125.56 138.43,123.02 137.79,122.39 133.34,122.39 133.34,126.2 135.88,128.74 135.88,133.19 133.98,135.09 128.27,135.09 128.27,145.89 127,147.16 113.03,147.16 111.76,145.89 IC4.10
  Bottom 0.254: v160.65,77.3 152.4,77.3 151.12,78.57 DAR8-11.7 148.59,78.57 v146.68,78.57 | v161.92,88.73 163.19,90 170.18,90 171.44,91.27 IC24.17 | IC4.10 111.76,143.34 110.48,142.08 86.36,142.08 84.45,143.98 IC3.10 83.18,143.98 81.91,142.71 67.31,142.71 66.67,142.08 53.34,142.08 | 53.34,142.08 55.24,143.98 IC2.10 | 53.34,142.08 52.06,140.81 31.75,140.81 28.57,143.98 IC1.10
DAR09  (via drill 0.61)
  Top 0.254: v34.92,65.88 33.65,67.14 33.65,108.42 31.75,110.32 31.75,138.27 26.03,143.98 IC1.11 | v177.8,147.79 v177.8,86.19 | v113.66,149.06 109.85,145.25 IC4.11
  Bottom 0.254: 174.62,85.56 174.62,83.02 173.99,82.38 152.4,82.38 151.12,81.11 DAR8-11.6 | 174.62,85.56 173.35,85.56 IC24.15 | 51.43,146.52 27.3,146.52 26.03,145.25 IC1.11 | 51.43,146.52 52.7,145.25 IC2.11 | 79.37,146.52 80.64,145.25 IC3.11 | 79.37,146.52 51.43,146.52 | 79.37,146.52 107.31,146.52 108.58,145.25 IC4.11 | v34.92,65.88 37.46,65.88 RS08.5 | 174.62,85.56 175.25,86.19 v177.8,86.19 | v177.8,147.79 176.53,149.06 v113.66,149.06
DAR10  (via drill 0.61)
  Top 0.254: v152.4,81.11 151.76,81.75 151.76,87.46 | 151.76,87.46 151.76,89.37 150.49,90.64 DAR8-11.2 | v44.45,88.1 43.17,86.83 43.17,62.7 41.27,60.8 RS08.10 | v92.7,89.37 95.25,91.91 95.25,114.77 97.79,117.31 97.79,120.48 95.25,123.02 v95.25,128.11 | v149.86,130.01 149.22,129.38 149.22,102.7 149.86,102.07 149.86,96.35 147.31,93.81 147.31,88.73 148.59,87.46 151.76,87.46
  Bottom 0.254: v152.4,81.11 153.66,79.84 166.37,79.84 167,80.48 170.81,80.48 171.44,81.11 IC24.13 | v44.45,88.1 45.71,89.37 v92.7,89.37 | v95.25,128.11 96.52,129.38 130.81,129.38 131.44,130.01 v149.86,130.01
DAR11  (via drill 0.61)
  Top 0.254: v154.3,73.49 154.3,83.65 152.4,85.56 152.4,92.54 148.59,92.54 147.95,91.91 147.95,90.64 149.22,89.37 DAR8-11.3 | v41.27,79.84 41.9,79.21 41.9,64.6 40,64.6 38.73,63.34 RS08.7 | v88.26,81.11 88.9,80.48 v88.9,37.94 | v168.27,36.66 168.27,58.89 167.63,59.52 167.63,70.95 172.08,75.4 IC24.11
  Bottom 0.254: v154.3,73.49 154.94,74.13 167.63,74.13 170.18,76.67 172.08,76.67 IC24.11 | v41.27,79.84 42.54,81.11 v88.26,81.11 | v88.9,37.94 89.53,37.3 120.65,37.3 123.82,34.12 133.98,34.12 134.62,34.76 142.87,34.76 143.5,34.12 164.46,34.12 167,36.66 v168.27,36.66
DATA00\
  Bottom 0.254: IC34.12 29.21,20.16 28.57,20.79 24.76,20.79 24.12,21.43 14.6,21.43 13.33,22.7 C35L.2
DATA01\
  Bottom 0.254: IC34.14 29.21,25.23 28.57,25.87 24.76,25.87 24.12,26.51 14.6,26.51 13.33,25.23 C35L.4
DATA02\
  Bottom 0.254: IC34.16 29.21,30.32 27.94,29.05 14.6,29.05 13.33,27.78 C35L.6
DATA03\
  Bottom 0.254: IC34.18 29.21,35.4 27.94,34.12 18.41,34.12 15.87,31.59 14.6,31.59 13.33,30.32 C35L.8
DATA04\  (via drill 0.61)
  Top 0.254: v13.96,64.6 13.96,34.76 12.69,33.49 C35L.10
  Bottom 0.254: v13.96,64.6 17.78,64.6 21.59,68.41 IC26.3
DATA05\  (via drill 0.61)
  Top 0.254: v10.79,62.06 8.88,60.16 8.88,39.84 12.69,36.03 C35L.12
  Bottom 0.254: v10.79,62.06 15.87,62.06 16.51,62.7 20.95,62.7 21.59,63.34 IC26.5
DATA06\  (via drill 0.61)
  Top 0.254: v11.42,56.98 11.42,39.84 12.69,38.57 C35L.14
  Bottom 0.254: v11.42,56.98 20.32,56.98 21.59,58.26 IC26.7
DATA07\
  Bottom 0.254: IC26.9 21.59,53.18 20.32,51.91 14.6,51.91 13.96,51.27 13.96,49.37 12.06,49.37 11.42,48.73 11.42,41.11 12.69,41.11 C35L.16
DATA08\  (via drill 0.61)
  Top 0.254: v28.57,45.55 28.57,51.27 29.84,52.54 IC26.12
  Bottom 0.254: v28.57,45.55 27.3,44.29 14.6,44.29 13.33,43.02 C35L.18
DATA09\  (via drill 0.61)
  Top 0.254: v26.03,58.26 25.39,57.62 v25.39,46.83
  Bottom 0.254: v26.03,58.26 29.21,58.26 IC26.14 | v25.39,46.83 14.6,46.83 13.33,48.09 C35L.22
DATA10\
  Bottom 0.254: IC26.16 29.21,63.34 27.94,62.06 18.41,62.06 15.87,59.52 12.06,59.52 8.88,56.35 8.88,49.37 10.79,49.37 12.06,50.63 C35L.24
DATA11\  (via drill 0.61)
  Top 0.254: v28.57,54.45 28.57,66.51 29.84,67.78 IC26.18
  Bottom 0.254: v28.57,54.45 14.6,54.45 13.33,53.18 C35L.26
DATA_IN  (via drill 0.61)
  Top 0.254: v153.66,100.8 154.94,99.53 v154.94,95.08 | v200.66,93.81 201.93,92.54 201.93,60.16 200.66,58.89 C36L.30
  Bottom 0.254: v153.66,100.8 148.59,100.8 147.95,101.43 146.05,101.43 144.78,100.16 118.11,100.16 114.93,96.99 IC22.6 | v154.94,95.08 184.15,95.08 185.41,93.81 v200.66,93.81
DCXA\
  Top 0.254: IC18.9 169.54,118.58 168.27,118.58 IC18.10
  Bottom 0.254: IC16.12 109.85,119.85 111.12,121.12 165.73,121.12 167,119.85 IC18.10
DIMA\  (via drill 0.61)
  Top 0.254: IC37.1 212.09,30.32 213.36,31.59 213.36,58.26 211.45,60.16 IC30.1 210.18,61.43 210.18,68.41 208.28,70.32 208.28,107.78 v201.93,114.13
  Bottom 0.254: v201.93,114.13 142.24,114.13 142.24,117.94 IC17.11 | IC30.19 217.16,58.26 215.9,59.52 213.36,59.52 212.09,60.8 IC30.1
DIML\  (via drill 0.61)
  Top 0.254: v140.97,102.7 140.97,116.67 139.69,117.94 IC17.12 | v196.84,90.64 196.84,67.14 196.21,66.51 196.21,22.06 200.02,18.25 INTENB.11
  Bottom 0.254: v140.97,102.7 141.6,103.34 147.31,103.34 147.95,103.97 163.83,103.97 165.09,102.7 199.38,102.7 209.55,92.54 | 209.55,92.54 212.72,92.54 216.53,88.73 216.53,87.46 219.71,87.46 220.34,86.83 220.34,76.67 219.07,76.67 FIELD.11 | v196.84,90.64 198.75,92.54 209.55,92.54
DIO00  (via drill 0.61)
  Top 0.254: v49.52,122.39 50.79,121.12 50.79,120.48 IC14.12 | v39.36,21.43 41.9,21.43 41.9,25.87 40.63,27.14 RS08.36 | IC13.12 22.86,117.94 21.59,116.67 21.59,74.77 20.95,74.13 20.95,24.6 22.22,23.33 IC34.8
  Bottom 0.254: v49.52,122.39 26.03,122.39 23.49,119.85 IC13.12 | IC34.8 24.12,22.7 25.39,21.43 v39.36,21.43 44.45,16.35 74.93,16.35 75.56,16.98 78.73,16.98 78.73,21.43 77.47,22.7 74.93,20.16 IC35.12
DIO01
  Top 0.254: IC14.11 53.34,117.94 49.52,114.13 49.52,41.74 48.25,40.48 48.25,26.51 41.9,20.16 37.46,20.16 37.46,21.43 36.82,22.06 36.82,23.33 38.09,24.6 RS08.37
  Bottom 0.254: IC13.11 26.03,119.85 27.3,121.12 51.43,121.12 52.7,119.85 IC14.11 | 40,26.51 67.31,26.51 67.94,25.87 71.75,25.87 72.39,25.23 IC35.14 | 40,26.51 38.73,25.23 RS08.37 | 40,26.51 25.39,26.51 24.12,27.78 IC34.6
DIO02  (via drill 0.61)
  Top 0.254: v56.51,34.12 56.51,53.18 57.14,53.81 57.14,116.67 55.88,117.94 IC14.10
  Bottom 0.254: IC13.10 28.57,118.58 30.48,116.67 54.6,116.67 55.88,117.94 IC14.10 | 33.65,31.59 25.39,31.59 24.12,32.86 IC34.4 | 33.65,31.59 37.46,27.78 RS08.35 | 33.65,31.59 41.27,31.59 43.81,34.12 v56.51,34.12 68.58,34.12 72.39,30.32 IC35.16
DIO03  (via drill 0.61)
  Top 0.254: v33.65,36.66 36.82,33.49 36.82,32.22 37.46,31.59 | 37.46,31.59 38.09,30.95 RS08.33 | v46.35,36.66 41.27,31.59 37.46,31.59 | IC13.9 30.48,117.94 29.21,116.67 29.21,88.1 27.3,86.19 27.3,55.72 26.03,54.45 26.03,47.46 26.67,46.83 26.67,41.74 23.49,38.57 IC34.2
  Bottom 0.254: IC13.9 31.11,118.58 32.38,117.31 40.63,117.31 42.54,119.21 43.81,119.21 44.45,118.58 44.45,117.31 53.97,117.31 54.6,117.94 54.6,121.12 56.51,121.12 57.78,119.85 IC14.9 | v33.65,36.66 25.39,36.66 24.12,37.94 IC34.2 | v46.35,36.66 71.12,36.66 72.39,35.4 IC35.18
DIO04  (via drill 0.61)
  Top 0.254: v69.21,68.41 v69.21,103.97 | v54.6,41.11 v54.6,67.14
  Bottom 0.254: IC26.17 31.75,65.88 33.02,67.14 v54.6,67.14 63.49,67.14 64.77,68.41 IC28.3 67.31,68.41 v69.21,68.41 | v69.21,103.97 69.84,103.97 76.2,110.32 IC15.2 | v54.6,41.11 53.97,41.74 42.54,41.74 41.27,43.02 RS08.24
DIO05  (via drill 0.61)
  Top 0.254: v66.67,105.24 66.67,78.57 68.58,76.67 68.58,69.05 67.94,68.41 67.94,65.24 66.67,63.97 IC28.5 | v34.28,41.74 33.65,42.38 33.65,57.62 31.11,60.16 IC26.15
  Bottom 0.254: IC26.15 31.75,60.8 33.02,62.06 63.49,62.06 64.77,63.34 IC28.5 | v66.67,105.24 67.31,105.24 73.02,110.96 IC15.1 | v34.28,41.74 38.73,41.74 40,40.48 RS08.26
DIO06  (via drill 0.61)
  Top 0.254: IC26.13 31.11,55.08 33.02,53.18 33.02,38.57 37.46,34.12 39.36,34.12 39.36,36.03 40.63,37.3 RS08.28 | v46.35,58.26 45.71,57.62 v45.71,40.48 | v59.68,58.26 v59.68,121.12
  Bottom 0.254: v46.35,58.26 v59.68,58.26 64.77,58.26 IC28.7 | v45.71,40.48 43.17,37.94 41.27,37.94 RS08.28 | v59.68,121.12 74.29,121.12 75.56,119.85 IC15.13
DIO07  (via drill 0.61)
  Top 0.254: IC15.12 78.1,119.85 76.83,121.12 72.39,121.12 72.39,79.21 70.48,77.3 70.48,69.68 71.75,68.41 71.75,58.89 66.67,53.81 IC28.9 | v31.11,43.02 31.11,50 IC26.11
  Bottom 0.254: IC26.11 31.75,50.63 33.02,51.91 63.49,51.91 64.77,53.18 IC28.9 | v31.11,43.02 37.46,36.66 38.73,36.66 40,35.4 RS08.30
DIO08  (via drill 0.61)
  Top 0.254: v87.62,56.98 87.62,71.59 86.99,72.22 86.99,84.92 87.62,85.56 87.62,121.12 83.18,121.12 81.91,119.85 IC15.11 | v43.17,56.98 43.17,36.03 40.63,33.49 RS08.32
  Bottom 0.254: IC26.8 24.12,55.72 25.39,56.98 v43.17,56.98 45.08,56.98 45.71,56.35 61.59,56.35 62.22,56.98 64.77,54.45 71.12,54.45 72.39,53.18 IC28.12 74.93,53.18 78.73,56.98 v87.62,56.98
DIO09  (via drill 0.61)
  Top 0.254: v78.73,58.26 82.55,62.06 82.55,116.67 83.81,117.94 IC15.10 | v34.92,59.52 35.55,58.89 35.55,38.57 38.09,36.03 RS08.29
  Bottom 0.254: IC26.6 24.12,60.8 25.39,59.52 v34.92,59.52 41.9,59.52 43.81,57.62 45.71,57.62 46.35,56.98 60.95,56.98 61.59,57.62 64.13,57.62 64.77,56.98 71.12,56.98 72.39,58.26 IC28.14 74.93,58.26 v78.73,58.26
DIO10  (via drill 0.61)
  Top 0.254: v80.01,121.12 78.1,121.12 77.47,121.75 69.21,121.75 69.21,105.24 70.48,103.97 69.84,103.34 69.84,69.05 70.48,68.41 v70.48,64.6 | v44.45,36.66 44.45,63.97 v45.08,64.6
  Bottom 0.254: IC26.4 24.12,65.88 25.39,64.6 v45.08,64.6 v70.48,64.6 71.12,64.6 72.39,63.34 IC28.16 | v80.01,121.12 84.45,121.12 85.72,119.85 IC15.9 | v44.45,36.66 40,36.66 38.73,37.94 RS08.27
DIO11  (via drill 0.61)
  Top 0.254: v77.47,117.31 74.93,114.77 74.93,74.77 75.56,74.13 75.56,70.32 74.29,69.05 IC28.18 | v36.19,69.68 36.19,43.02 38.09,41.11 RS08.25
  Bottom 0.254: IC26.2 24.12,70.95 25.39,69.68 v36.19,69.68 71.12,69.68 72.39,68.41 IC28.18 | v77.47,117.31 86.99,117.31 88.26,118.58 IC15.8
DIOEVEN  (via drill 0.61)
  Top 0.254: v62.22,27.78 62.22,23.96 65.4,20.79 IC35.9 | v42.54,115.4 44.45,113.5 44.45,100.16 46.98,97.62 46.98,58.89 47.62,58.26 47.62,36.66 41.27,30.32 RS08.34
  Bottom 0.254: v62.22,27.78 60.95,29.05 42.54,29.05 41.27,30.32 RS08.34 | v42.54,115.4 41.9,116.04 29.84,116.04 28.57,117.31 22.22,117.31 20.95,118.58 IC13.13
DMA00  (via drill 0.61)
  Top 0.254: v57.78,53.18 60.32,50.63 60.32,20.79 v71.12,10
  Bottom 0.254: IC38.8 163.83,12.54 162.56,11.27 137.16,11.27 135.88,10 DMA0-3.7 133.34,10 v71.12,10 | v57.78,53.18 41.27,53.18 RS08.16
DMA01  (via drill 0.61)
  Top 0.254: v50.79,45.55 52.7,43.65 v52.7,11.27
  Bottom 0.254: IC38.6 163.83,17.62 162.56,16.35 132.71,16.35 132.71,14.44 133.98,13.17 DMA0-3.6 133.34,12.54 132.08,11.27 v52.7,11.27 | v50.79,45.55 43.81,45.55 41.27,48.09 RS08.20
DMA02  (via drill 0.61)
  Top 0.254: v62.22,55.72 62.86,55.08 62.86,28.41 64.77,26.51 71.12,26.51 v71.12,22.7 | v130.81,20.16 133.34,22.7 DMA0-3.2
  Bottom 0.254: DMA0-3.2 135.88,22.7 137.16,21.43 162.56,21.43 163.83,22.7 IC38.4 | v62.22,55.72 41.27,55.72 RS08.14 | v71.12,22.7 72.39,21.43 74.93,21.43 76.83,23.33 81.28,23.33 84.45,20.16 v130.81,20.16
DMA03  (via drill 0.61)
  Top 0.254: v42.54,60.16 42.54,59.52 41.27,58.26 RS08.12 | v50.79,59.52 53.97,56.35 53.97,41.74 53.34,41.11 53.34,18.89 v67.31,4.92 | v136.52,4.28 136.52,18.25 135.25,19.52 DMA0-3.3
  Bottom 0.254: DMA0-3.3 133.98,20.79 132.71,22.06 132.71,23.96 135.88,23.96 139.69,27.78 139.69,29.05 162.56,29.05 163.83,27.78 IC38.2 | v42.54,60.16 43.17,59.52 v50.79,59.52 | v67.31,4.92 68.58,3.65 120.65,3.65 121.28,4.28 v136.52,4.28
DMA04  (via drill 0.61)
  Top 0.254: v158.11,36.66 161.28,39.84 v161.28,43.02 | v34.92,60.8 32.38,63.34 v32.38,79.84 | v88.26,84.92 90.17,83.02 v90.17,58.26
  Bottom 0.254: v158.11,36.66 143.5,36.66 135.88,44.29 DMA4-7.7 133.34,44.29 128.27,49.37 123.82,49.37 120.65,52.54 113.03,52.54 109.85,55.72 92.7,55.72 v90.17,58.26 | v161.28,43.02 164.46,46.19 IC31.8 | v34.92,60.8 37.46,60.8 RS08.9 | v32.38,79.84 37.46,84.92 v88.26,84.92
DMA05  (via drill 0.61)
  Top 0.254: v154.94,44.29 156.21,45.55 161.92,45.55 v161.92,51.91 | v36.82,74.77 36.82,70.32 37.46,69.68 36.82,69.05 36.82,60.16 38.09,58.89 RS08.11 | v135.88,69.68 137.79,67.78 137.79,50 135.25,47.46 DMA4-7.6
  Bottom 0.254: v154.94,44.29 153.03,44.29 151.76,43.02 139.69,43.02 135.88,46.83 DMA4-7.6 | v161.92,51.91 163.83,51.91 IC31.6 | v36.82,74.77 92.07,74.77 95.88,70.95 122.55,70.95 123.82,69.68 v135.88,69.68
DMA06  (via drill 0.61)
  Top 0.254: v39.36,49.37 39.36,53.81 38.09,55.08 RS08.13 | v114.3,48.09 118.74,52.54 v118.74,56.98
  Bottom 0.254: IC31.4 163.83,56.98 162.56,55.72 137.16,55.72 135.88,56.98 DMA4-7.2 133.34,56.98 v118.74,56.98 | v39.36,49.37 63.49,49.37 65.4,47.46 82.55,47.46 83.18,46.83 100.96,46.83 102.23,48.09 v114.3,48.09
DMA07  (via drill 0.61)
  Top 0.254: v136.52,64.6 137.16,63.97 137.16,56.98 135.25,55.08 DMA4-7.3 | v164.46,67.14 165.73,65.88 167,65.88 167,63.97 165.73,62.7 IC31.2 | v50.79,54.45 52.7,52.54 v52.7,48.09 | v130.17,44.29 129.53,44.92 129.53,49.37 128.9,50 v128.9,52.54
  Bottom 0.254: v136.52,64.6 137.16,65.24 160.02,65.24 161.92,67.14 v164.46,67.14 | v50.79,54.45 40,54.45 38.73,53.18 RS08.15 | v52.7,48.09 55.88,44.92 74.93,44.92 80.64,39.2 94.61,39.2 95.25,38.57 118.11,38.57 123.82,44.29 v130.17,44.29 | v128.9,52.54 130.81,54.45 133.34,54.45 DMA4-7.3
DMA08  (via drill 0.61)
  Top 0.254: v159.38,84.92 160.65,83.65 v160.65,81.11 | v19.68,49.37 20.32,50 v20.32,76.03
  Bottom 0.254: v159.38,84.92 140.97,84.92 135.25,79.21 DMA8-11.7 133.98,77.94 130.81,77.94 130.17,78.57 122.55,78.57 121.92,77.94 92.7,77.94 92.07,78.57 22.86,78.57 v20.32,76.03 | v160.65,81.11 163.83,81.11 IC24.8 | v19.68,49.37 36.19,49.37 37.46,50.63 RS08.17
DMA09  (via drill 0.61)
  Top 0.254: v131.44,81.11 132.08,81.75 v132.08,96.99 | v160.02,98.26 160.65,97.62 v160.65,86.19 | v64.13,39.2 63.49,39.84 63.49,79.21 v62.86,79.84
  Bottom 0.254: v132.08,96.99 133.34,98.26 v160.02,98.26 | v160.65,86.19 163.83,86.19 IC24.6 | DMA8-11.6 133.34,81.11 v131.44,81.11 123.19,81.11 120.65,78.57 93.34,78.57 92.7,79.21 63.49,79.21 v62.86,79.84 | v64.13,39.2 60.95,42.38 43.17,42.38 41.27,44.29 39.36,44.29 39.36,46.19 38.09,47.46 RS08.19
DMA10  (via drill 0.61)
  Top 0.254: v32.38,90 27.94,85.56 27.94,55.08 27.3,54.45 v27.3,48.09 | v154.3,92.54 152.4,94.45 152.4,113.5 v150.49,115.4 | v144.78,115.4 143.5,114.13 143.5,100.8 139.06,96.35 v139.06,93.81
  Bottom 0.254: v32.38,90 81.28,90 81.91,90.64 132.71,90.64 133.34,91.27 DMA8-11.2 135.88,91.27 136.52,91.27 v139.06,93.81 | v27.3,48.09 29.84,45.55 37.46,45.55 RS08.21 | v154.3,92.54 162.56,92.54 163.83,91.27 IC24.4 | v150.49,115.4 v144.78,115.4
DMA11  (via drill 0.61)
  Top 0.254: v161.92,96.35 v161.92,90 | v44.45,82.38 43.81,81.75 43.81,59.52 41.9,57.62 41.9,44.29 40,44.29 38.73,43.02 RS08.23 | v136.52,84.92 136.52,86.83 135.25,88.1 DMA8-11.3
  Bottom 0.254: v161.92,90 137.16,90 135.88,88.73 DMA8-11.3 | v161.92,96.35 163.83,96.35 IC24.2 | v44.45,82.38 45.71,83.65 109.85,83.65 111.12,84.92 130.81,84.92 133.34,82.38 135.88,82.38 136.52,83.02 v136.52,84.92
DMA-IN\
  Top 0.254: IC34.1 22.86,41.11 22.86,48.09 24.76,50 24.76,71.59 23.49,72.86 IC26.1 22.86,74.13 22.86,107.78 25.39,110.32 IC13.4
  Bottom 0.254: IC26.19 29.21,70.95 26.67,73.49 24.12,73.49 IC26.1 | IC41.12 88.26,14.44 86.36,12.54 74.93,12.54 74.29,13.17 20.32,13.17 11.42,22.06 11.42,39.2 20.32,39.2 21.59,40.48 IC34.1
DMA-OUT\  (via drill 0.61)
  Top 0.254: v91.44,29.68 91.44,21.43 96.52,16.35 IC41.9 | IC28.1 65.4,72.86 64.13,71.59 64.13,42.38 65.4,41.11 IC35.1
  Bottom 0.254: IC28.1 67.31,73.49 69.84,70.95 72.39,70.95 IC28.19 | IC35.1 67.31,40.48 69.84,40.48 72.39,37.94 IC35.19 74.93,37.94 75.56,37.94 79.37,34.12 86.99,34.12 v91.44,29.68
DONE  (via drill 0.61)
  Top 0.254: v159.38,18.89 163.19,15.08 163.19,6.82 163.83,6.18 187.96,6.18 187.96,7.46 189.22,8.73 189.22,11.27 193.67,15.71 204.47,15.71 204.47,110.32 198.12,116.67 198.12,117.94 IC11.9
  Bottom 0.254: v159.38,18.89 152.4,18.89 151.12,20.16 IC40.2
DRV01\
  Top 0.254: IC41.4 85.72,8.09 84.45,9.36 80.64,9.36 80.01,8.73 80.01,6.18 77.47,3.65 36.82,3.65 36.82,20.79 36.19,21.43 36.19,25.23 37.46,26.51 40,26.51 40,25.23 RS08.38
DRV23\  (via drill 0.61)
  Top 0.254: v77.47,4.92 77.47,20.16 78.73,21.43 v78.73,38.57
  Bottom 0.254: v77.47,4.92 91.44,4.92 93.34,6.82 IC41.7 | v78.73,38.57 73.02,44.29 42.54,44.29 41.27,45.55 RS08.22
DRVOK\  (via drill 0.61)
  Top 0.254: IC21.13 80.64,103.34 79.37,103.34 IC21.14 78.73,102.7 80.01,101.43 80.01,61.43 77.47,58.89 v77.47,21.43
  Bottom 0.254: 43.81,18.89 40.63,22.06 RS08.40 | 43.81,18.89 45.08,17.62 R2.1 | v77.47,21.43 74.93,18.89 43.81,18.89
EIE  (via drill 0.61)
  Top 0.254: v197.48,6.82 200.02,9.36 INTENB.6
  Bottom 0.254: IC40.9 158.75,10 160.02,8.73 184.15,8.73 186.05,6.82 v197.48,6.82 198.12,6.18 214.62,6.18 217.16,8.73 220.34,8.73 220.34,25.87 219.71,26.51 217.16,26.51 216.53,27.14 212.72,27.14 212.09,27.78 IC37.2
ERROR  (via drill 0.61)
  Top 0.254: v207,96.35 207,2.38 166.37,2.38 162.56,6.18 162.56,7.46 158.11,11.9 IC40.10
  Bottom 0.254: v207,96.35 209.55,98.89 IC12.6 210.18,99.53 208.91,99.53 208.91,102.07 209.55,102.7 215.26,102.7 215.26,116.67 211.45,120.48 210.18,120.48 204.47,126.2 187.32,126.2 186.05,124.93 IC7.2
EXAD0\
  Top 0.254: IC20.9 9.52,83.02 8.25,81.75 8.25,68.41 12.69,63.97 C35L.34
EXAD1\
  Top 0.254: IC20.7 10.79,88.1 12.06,86.83 12.06,72.22 11.42,71.59 11.42,67.78 12.69,66.51 C35L.36
EXAD2\
  Top 0.254: IC20.5 10.79,93.18 13.96,90 13.96,70.32 12.69,69.05 C35L.38
F.1  (via drill 0.61)
  Top 0.254: v208.91,68.41 208.91,44.92 210.18,43.65 IC30.8 210.18,42.38 207.64,39.84 207.64,1.74 165.73,1.74 160.02,7.46 160.02,8.73 156.21,8.73 155.57,9.36 155.57,16.35 v154.3,17.62
  Bottom 0.254: v208.91,68.41 210.18,69.68 219.71,69.68 220.34,70.32 220.34,74.77 217.16,74.77 212.72,79.21 212.72,83.02 211.45,83.02 FIELD.3 | v154.3,17.62 152.4,17.62 151.12,18.89 133.34,18.89 126.36,11.9 74.29,11.9 73.66,12.54 8.25,12.54 8.25,81.75 8.88,82.38 15.23,82.38 16.51,81.11 IC20.11
F.2
  Top 0.254: IC30.11 219.07,38.57 220.34,39.84 220.34,90 217.8,92.54 213.36,92.54 213.36,88.73 211.45,86.83 FIELD.2
  Bottom 0.254: IC20.13 19.05,86.19 19.68,86.83 132.71,86.83 133.34,87.46 184.15,87.46 185.41,86.19 209.55,86.19 FIELD.2
F.3  (via drill 0.61)
  Top 0.254: IC30.13 217.8,43.65 216.53,44.92 v216.53,54.45 216.53,62.06 212.72,65.88 212.72,74.13 211.45,75.4 FIELD.6
  Bottom 0.254: v216.53,54.45 222.88,54.45 222.88,130.65 211.45,142.08 126.36,142.08 121.28,147.16 8.25,147.16 8.25,126.2 12.06,122.39 12.69,122.39 12.69,96.35 17.14,91.91 IC20.15
GND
